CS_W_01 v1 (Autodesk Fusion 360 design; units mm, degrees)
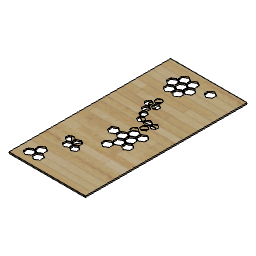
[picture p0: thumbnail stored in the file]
description: Part Number
part number: CS_W_01
base_feature "Base Feature"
